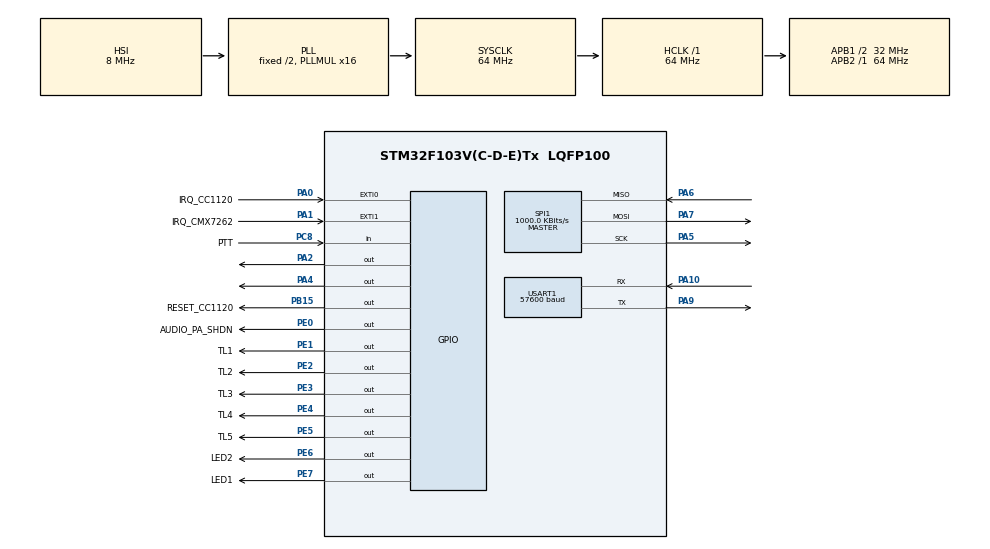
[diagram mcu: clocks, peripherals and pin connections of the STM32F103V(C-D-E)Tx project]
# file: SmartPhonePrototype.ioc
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Dma.Request0=USART1_RX
Dma.Request1=USART1_TX
Dma.Request2=SPI1_RX
Dma.Request3=SPI1_TX
Dma.SPI1_RX.2.Direction=DMA_PERIPH_TO_MEMORY
Dma.SPI1_RX.2.Instance=DMA1_Channel2
Dma.SPI1_RX.2.MemDataAlignment=DMA_MDATAALIGN_BYTE
Dma.SPI1_RX.2.MemInc=DMA_MINC_ENABLE
Dma.SPI1_RX.2.Mode=DMA_NORMAL
Dma.SPI1_RX.2.PeriphDataAlignment=DMA_PDATAALIGN_BYTE
Dma.SPI1_RX.2.PeriphInc=DMA_PINC_DISABLE
Dma.SPI1_RX.2.Priority=DMA_PRIORITY_LOW
Dma.SPI1_TX.3.Direction=DMA_MEMORY_TO_PERIPH
Dma.SPI1_TX.3.Instance=DMA1_Channel3
Dma.SPI1_TX.3.MemDataAlignment=DMA_MDATAALIGN_BYTE
Dma.SPI1_TX.3.MemInc=DMA_MINC_ENABLE
Dma.SPI1_TX.3.Mode=DMA_NORMAL
Dma.SPI1_TX.3.PeriphDataAlignment=DMA_PDATAALIGN_BYTE
Dma.SPI1_TX.3.PeriphInc=DMA_PINC_DISABLE
Dma.SPI1_TX.3.Priority=DMA_PRIORITY_LOW
Dma.USART1_RX.0.Direction=DMA_PERIPH_TO_MEMORY
Dma.USART1_RX.0.Instance=DMA1_Channel5
Dma.USART1_RX.0.MemDataAlignment=DMA_MDATAALIGN_BYTE
Dma.USART1_RX.0.MemInc=DMA_MINC_ENABLE
Dma.USART1_RX.0.Mode=DMA_NORMAL
Dma.USART1_RX.0.PeriphDataAlignment=DMA_PDATAALIGN_BYTE
Dma.USART1_RX.0.PeriphInc=DMA_PINC_DISABLE
Dma.USART1_RX.0.Priority=DMA_PRIORITY_LOW
Dma.USART1_TX.1.Direction=DMA_MEMORY_TO_PERIPH
Dma.USART1_TX.1.Instance=DMA1_Channel4
Dma.USART1_TX.1.MemDataAlignment=DMA_MDATAALIGN_BYTE
Dma.USART1_TX.1.MemInc=DMA_MINC_ENABLE
Dma.USART1_TX.1.Mode=DMA_NORMAL
Dma.USART1_TX.1.PeriphDataAlignment=DMA_PDATAALIGN_BYTE
Dma.USART1_TX.1.PeriphInc=DMA_PINC_DISABLE
Dma.USART1_TX.1.Priority=DMA_PRIORITY_LOW
Mcu.Family=STM32F1
Mcu.Name=STM32F103V(C-D-E)Tx
Mcu.Package=LQFP100
NVIC.DMA1_Channel2_IRQn=true\:0\:0\:false
NVIC.DMA1_Channel3_IRQn=true\:0\:0\:false
NVIC.DMA1_Channel4_IRQn=true\:0\:0\:false
NVIC.DMA1_Channel5_IRQn=true\:0\:0\:false
NVIC.EXTI0_IRQn=true\:0\:0\:false
NVIC.EXTI1_IRQn=true\:0\:0\:false
NVIC.PriorityGroup=NVIC_PRIORITYGROUP_4
NVIC.RCC_IRQn=true\:0\:0\:false
NVIC.SPI1_IRQn=true\:0\:0\:false
NVIC.USART1_IRQn=true\:0\:0\:false
PA0-WKUP.GPIO_Label=IRQ_CC1120
PA0-WKUP.GPIO_ModeDefaultEXTI=GPIO_MODE_IT_FALLING
PA0-WKUP.GPIO_PuPd=GPIO_PULLUP
PA0-WKUP.Signal=GPXTI0
PA1.GPIO_Label=IRQ_CMX7262
PA1.GPIO_ModeDefaultEXTI=GPIO_MODE_IT_FALLING
PA1.GPIO_PuPd=GPIO_PULLUP
PA1.Signal=GPXTI1
PA10.Mode=Asynchronous
PA10.Signal=USART1_RX
PA2.GPIO_Speed=GPIO_SPEED_HIGH
PA2.Signal=GPIO_Output
PA4.GPIO_Speed=GPIO_SPEED_HIGH
PA4.Signal=GPIO_Output
PA5.Mode=Full_Duplex_Master
PA5.Signal=SPI1_SCK
PA6.Mode=Full_Duplex_Master
PA6.Signal=SPI1_MISO
PA7.Mode=Full_Duplex_Master
PA7.Signal=SPI1_MOSI
PA9.Mode=Asynchronous
PA9.Signal=USART1_TX
PB15.GPIO_Label=RESET_CC1120
PB15.Signal=GPIO_Output
PC8.GPIO_Label=PTT
PC8.Signal=GPIO_Input
PE0.GPIO_Label=AUDIO_PA_SHDN
PE0.GPIO_Speed=GPIO_SPEED_HIGH
PE0.Signal=GPIO_Output
PE1.GPIO_Label=TL1
PE1.Signal=GPIO_Output
PE2.GPIO_Label=TL2
PE2.Signal=GPIO_Output
PE3.GPIO_Label=TL3
PE3.Signal=GPIO_Output
PE4.GPIO_Label=TL4
PE4.Signal=GPIO_Output
PE5.GPIO_Label=TL5
PE5.Signal=GPIO_Output
PE6.GPIO_Label=LED2
PE6.GPIO_Speed=GPIO_SPEED_HIGH
PE6.Signal=GPIO_Output
PE7.GPIO_Label=LED1
PE7.GPIO_Speed=GPIO_SPEED_HIGH
PE7.Signal=GPIO_Output
ProjectManager.TargetToolchain=MDK-ARM V5
RCC.AHBFreq_Value=64000000
RCC.APB1CLKDivider=RCC_HCLK_DIV2
RCC.APB1Freq_Value=32000000
RCC.APB1TimFreq_Value=64000000
RCC.APB2Freq_Value=64000000
RCC.APB2TimFreq_Value=64000000
RCC.HCLKFreq_Value=64000000
RCC.PLLMUL=RCC_PLL_MUL16
RCC.SYSCLKFreq_VALUE=64000000
RCC.SYSCLKSource=RCC_SYSCLKSOURCE_PLLCLK
RCC.USBFreq_Value=64000000
SPI1.BaudRatePrescaler=SPI_BAUDRATEPRESCALER_64
SPI1.CalculateBaudRate=1000.0 KBits/s
SPI1.Mode=SPI_MODE_MASTER
TIM2.Period=65535
TIM2.TIM_MasterOutputTrigger=TIM_TRGO_UPDATE
TIM2.TIM_MasterSlaveMode=TIM_MASTERSLAVEMODE_ENABLE
TIM3.Period=65535
TIM3.TIM_MasterSlaveMode=TIM_MASTERSLAVEMODE_DISABLE
TIM4.Period=65535
TIM5.Period=65535
USART1.BaudRate=57600
VP_TIM2_VS_ClockSourceINT.Mode=Internal
VP_TIM3_VS_ClockSourceITR.Mode=TriggerSource_ITR1
VP_TIM3_VS_ControllerModeClock.Mode=Clock Mode
VP_TIM4_VS_ClockSourceINT.Mode=Internal
VP_TIM5_VS_ClockSourceINT.Mode=Internal
board=SmartPhonePrototype

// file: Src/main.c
/**
  ******************************************************************************
  * File Name          : main.c
  * Description        : Main program body
  ******************************************************************************
  *
  * COPYRIGHT(c) 2016 STMicroelectronics
  *
  * Redistribution and use in source and binary forms, with or without modification,
  * are permitted provided that the following conditions are met:
  *   1. Redistributions of source code must retain the above copyright notice,
  *      this list of conditions and the following disclaimer.
  *   2. Redistributions in binary form must reproduce the above copyright notice,
  *      this list of conditions and the following disclaimer in the documentation
  *      and/or other materials provided with the distribution.
  *   3. Neither the name of STMicroelectronics nor the names of its contributors
  *      may be used to endorse or promote products derived from this software
  *      without specific prior written permission.
  *
  * THIS SOFTWARE IS PROVIDED BY THE COPYRIGHT HOLDERS AND CONTRIBUTORS "AS IS"
  * AND ANY EXPRESS OR IMPLIED WARRANTIES, INCLUDING, BUT NOT LIMITED TO, THE
  * IMPLIED WARRANTIES OF MERCHANTABILITY AND FITNESS FOR A PARTICULAR PURPOSE ARE
  * DISCLAIMED. IN NO EVENT SHALL THE COPYRIGHT HOLDER OR CONTRIBUTORS BE LIABLE
  * FOR ANY DIRECT, INDIRECT, INCIDENTAL, SPECIAL, EXEMPLARY, OR CONSEQUENTIAL
  * DAMAGES (INCLUDING, BUT NOT LIMITED TO, PROCUREMENT OF SUBSTITUTE GOODS OR
  * SERVICES; LOSS OF USE, DATA, OR PROFITS; OR BUSINESS INTERRUPTION) HOWEVER
  * CAUSED AND ON ANY THEORY OF LIABILITY, WHETHER IN CONTRACT, STRICT LIABILITY,
  * OR TORT (INCLUDING NEGLIGENCE OR OTHERWISE) ARISING IN ANY WAY OUT OF THE USE
  * OF THIS SOFTWARE, EVEN IF ADVISED OF THE POSSIBILITY OF SUCH DAMAGE.
  *
  ******************************************************************************
  */
#include "stm32f1xx_hal.h"

/* USER CODE BEGIN Includes */
#include "globals.h"
#include "cc1120.h"
#include "cmx7262.h"
#include "ProcessStates.h"
#include "SPIMLogic.h"
/* USER CODE END Includes */

SPI_HandleTypeDef hspi1;
DMA_HandleTypeDef hdma_spi1_rx;
DMA_HandleTypeDef hdma_spi1_tx;

TIM_HandleTypeDef htim2;
TIM_HandleTypeDef htim3;
TIM_HandleTypeDef htim4;
TIM_HandleTypeDef htim5;

UART_HandleTypeDef huart1;
DMA_HandleTypeDef hdma_usart1_rx;
DMA_HandleTypeDef hdma_usart1_tx;

/* USER CODE BEGIN PV */
/* Private variables ---------------------------------------------------------*/
extern UART_InitTypeDef DefaultUARTParams;

extern en_UARTstates UARTstate;

#define DMA_UART_PRIORITY (2)

/* USER CODE END PV */

void SystemClock_Config(void);
static void MX_GPIO_Init(void);
static void MX_DMA_Init(void);
static void MX_SPI1_Init(void);
static void MX_TIM2_Init(void);
static void MX_TIM3_Init(void);
static void MX_TIM4_Init(void);
static void MX_TIM5_Init(void);
static void MX_USART1_UART_Init(void);

/* USER CODE BEGIN PFP */
/* Private function prototypes -----------------------------------------------*/

/* USER CODE END PFP */

int main(void)
{
  /* USER CODE BEGIN 1 */
	#ifdef DEBUG_TRELLIS_CODER
	//TestTrellisCoder1_2();
	TestTrellisCoder3_4();
	#endif
  /* USER CODE END 1 */

  /* MCU Configuration----------------------------------------------------------*/

  /* Reset of all peripherals, Initializes the Flash interface and the Systick. */
  HAL_Init();

  /* Configure the system clock */
  SystemClock_Config();

  /* Initialize all configured peripherals */
  MX_GPIO_Init();
  MX_DMA_Init();
  MX_SPI1_Init();
  MX_TIM2_Init();
  MX_TIM3_Init();
  MX_TIM4_Init();
  MX_TIM5_Init();
  MX_USART1_UART_Init();

  /* USER CODE BEGIN 2 */
	// Устанавливаем CS периферийных микросхем в высокое состояние
	CC1120_CSN_HIGH();
	CMX7262_CSN_HIGH();

	// Pin Reset CC1120 устанавливаем в высокое состояние для перевода микросхемы в активное состояние
	CC1120_START();

	//Выключаем светодиоды
	LEDS_OFF();

	#ifdef DEBUG_USE_TL_LINES
	TLS_LOW();
	#endif

	//Запускаем таймеры для работы с периферией
	StartPeriphTimers();

	// Инициализируем работу по UART
	UART_InitInterface(&huart1);

	#ifdef DEBUG_CHECK_PERIPH_MODULES_ON_STARTUP	//Проверка работоспособности периферийных модулей
	CC1120_CheckModule(&hspi1);
	CMX7262_CheckModule(&hspi1);
	#endif

	//Делаем инициализацию радиомодуля для возможности управления его режимами и параметрами
	RadioModuleInit(&hspi1,&hspi1);

	#ifdef TEST_CMX7262
	CMX7262_TestMode();
	#endif

	#ifdef USE_LEDS
	//Сигнализируем о том, что модуль загрузился
	LED1_ON();
	#endif
  /* USER CODE END 2 */

  /* Infinite loop */
  /* USER CODE BEGIN WHILE */
  while (1)
  {
		//Если из UART приняты данные
		if(UARTstate==UART_DATA_RX_NEED_TO_PROCESS)
		{
			//Обрабатываем их
			ProcessDataFromExtDev();

			//Указываем, что данные обработаны
			UARTstate = UART_IDLE;
		}

		//Передача асинхронных данных (без непосредственного запроса от внешнего устройства)
		ProcessAsyncData();

		//Обработка состояния модуля CMX7262: передача/прием/тест
		ProcessCMX7262State();

		#ifndef TEST_CMX7262
		//Обрабатываем тангенту
		ProcessPTTState();

		ProcessRadioState();
		#endif

  /* USER CODE END WHILE */

  }

}

/** System Clock Configuration
*/
void SystemClock_Config(void)
{

  RCC_OscInitTypeDef RCC_OscInitStruct;
  RCC_ClkInitTypeDef RCC_ClkInitStruct;

  RCC_OscInitStruct.OscillatorType = RCC_OSCILLATORTYPE_HSI;
  RCC_OscInitStruct.HSIState = RCC_HSI_ON;
  RCC_OscInitStruct.HSICalibrationValue = 16;
  RCC_OscInitStruct.PLL.PLLState = RCC_PLL_ON;
  RCC_OscInitStruct.PLL.PLLSource = RCC_PLLSOURCE_HSI_DIV2;
  RCC_OscInitStruct.PLL.PLLMUL = RCC_PLL_MUL16;
  HAL_RCC_OscConfig(&RCC_OscInitStruct);

  RCC_ClkInitStruct.ClockType = RCC_CLOCKTYPE_SYSCLK|RCC_CLOCKTYPE_PCLK1;
  RCC_ClkInitStruct.SYSCLKSource = RCC_SYSCLKSOURCE_PLLCLK;
  RCC_ClkInitStruct.AHBCLKDivider = RCC_SYSCLK_DIV1;
  RCC_ClkInitStruct.APB1CLKDivider = RCC_HCLK_DIV2;
  RCC_ClkInitStruct.APB2CLKDivider = RCC_HCLK_DIV1;
  HAL_RCC_ClockConfig(&RCC_ClkInitStruct, FLASH_LATENCY_2);

  HAL_SYSTICK_Config(HAL_RCC_GetHCLKFreq()/1000);

  HAL_SYSTICK_CLKSourceConfig(SYSTICK_CLKSOURCE_HCLK);

  /* SysTick_IRQn interrupt configuration */
  HAL_NVIC_SetPriority(SysTick_IRQn, 0, 0);
}

/* SPI1 init function */
void MX_SPI1_Init(void)
{

  hspi1.Instance = SPI1;
  hspi1.Init.Mode = SPI_MODE_MASTER;
  hspi1.Init.Direction = SPI_DIRECTION_2LINES;						// режим работы: двухпроводный full duplex
  hspi1.Init.DataSize = SPI_DATASIZE_8BIT;								// размер данных - 8 бит
  hspi1.Init.CLKPolarity = SPI_POLARITY_LOW;
  hspi1.Init.CLKPhase = SPI_PHASE_1EDGE;									// синхронизация по заднему фронту
  hspi1.Init.NSS = SPI_NSS_SOFT;													// программный CS (аппаратный (SPI_NSS_HARD_OUTPUT) не понятно, как задействовать)
	hspi1.Init.BaudRatePrescaler = SPI_BAUDRATEPRESCALER_128 ;	//предделитель частоты SPI: 64МГц/128 = 500 кГц
  hspi1.Init.FirstBit = SPI_FIRSTBIT_MSB;									// старший бит - первый
  hspi1.Init.TIMode = SPI_TIMODE_DISABLED;
  hspi1.Init.CRCCalculation = SPI_CRCCALCULATION_DISABLED;// CRC не вычисляется
  hspi1.Init.CRCPolynomial = 10;
  HAL_SPI_Init(&hspi1);

}

/* Таймеры TIM2 и TIM3 реализуют высокоточный (точность - 1мкс) 32-битный таймер для оценки временных
интервалов в реализации низкоуровневых функций (передача байта по SPI, UART и т.п.) */

/* TIM2 init function */
void MX_TIM2_Init(void)
{

  TIM_ClockConfigTypeDef sClockSourceConfig;
  TIM_MasterConfigTypeDef sMasterConfig;

  htim2.Instance = TIM2;
  htim2.Init.Prescaler = (uint16_t) ((SystemCoreClock) / 1e6) - 1;		//такт таймера - в 1 мкс
  htim2.Init.CounterMode = TIM_COUNTERMODE_UP;
  htim2.Init.Period = 65535;
  htim2.Init.ClockDivision = TIM_CLOCKDIVISION_DIV1;
  HAL_TIM_Base_Init(&htim2);

  sClockSourceConfig.ClockSource = TIM_CLOCKSOURCE_INTERNAL;
  HAL_TIM_ConfigClockSource(&htim2, &sClockSourceConfig);

	//Таймер используется как master в каскадной цепочке таймеров для реализации 32-битного таймера
	//Слейвом выступает TIM3. Формируем для него сигнал тригера по истечению периода
  sMasterConfig.MasterOutputTrigger = TIM_TRGO_UPDATE;
  sMasterConfig.MasterSlaveMode = TIM_MASTERSLAVEMODE_ENABLE;
  HAL_TIMEx_MasterConfigSynchronization(&htim2, &sMasterConfig);

}

/* TIM3 init function */
void MX_TIM3_Init(void)
{

  TIM_SlaveConfigTypeDef sSlaveConfig;
  TIM_MasterConfigTypeDef sMasterConfig;

  htim3.Instance = TIM3;
  htim3.Init.Prescaler = 0;
  htim3.Init.CounterMode = TIM_COUNTERMODE_UP;
  htim3.Init.Period = 65535;
  htim3.Init.ClockDivision = TIM_CLOCKDIVISION_DIV1;
  HAL_TIM_Base_Init(&htim3);

	//Таймер используется как slave в каскадной цепочке таймеров для реализации 32-битного таймера
	//По переполнению счетчика master-таймера (TIM2) инкрементируется счетчик данного slave-таймера
	//Прерывание ITR1 используется как внешний тригер для инкрементирования значения счетчика
  sSlaveConfig.SlaveMode = TIM_SLAVEMODE_EXTERNAL1;
  sSlaveConfig.InputTrigger = TIM_TS_ITR1;
  HAL_TIM_SlaveConfigSynchronization(&htim3, &sSlaveConfig);

  sMasterConfig.MasterOutputTrigger = TIM_TRGO_RESET;
  sMasterConfig.MasterSlaveMode = TIM_MASTERSLAVEMODE_DISABLE;
  HAL_TIMEx_MasterConfigSynchronization(&htim3, &sMasterConfig);

}

/* TIM4 init function */
void MX_TIM4_Init(void)
{

  TIM_ClockConfigTypeDef sClockSourceConfig;
  TIM_MasterConfigTypeDef sMasterConfig;

  htim4.Instance = TIM4;
  htim4.Init.Prescaler = (uint16_t) ((SystemCoreClock)/1e5 - 1);	//такт таймера - в 10 мкс
  htim4.Init.CounterMode = TIM_COUNTERMODE_UP;
  htim4.Init.Period = 65535;
  htim4.Init.ClockDivision = TIM_CLOCKDIVISION_DIV1;
  HAL_TIM_Base_Init(&htim4);

  sClockSourceConfig.ClockSource = TIM_CLOCKSOURCE_INTERNAL;
  HAL_TIM_ConfigClockSource(&htim4, &sClockSourceConfig);

  sMasterConfig.MasterOutputTrigger = TIM_TRGO_RESET;
  sMasterConfig.MasterSlaveMode = TIM_MASTERSLAVEMODE_DISABLE;
  HAL_TIMEx_MasterConfigSynchronization(&htim4, &sMasterConfig);

}

/* TIM5 init function */
void MX_TIM5_Init(void)
{

  TIM_ClockConfigTypeDef sClockSourceConfig;
  TIM_MasterConfigTypeDef sMasterConfig;

  htim5.Instance = TIM5;
  htim5.Init.Prescaler = (uint16_t) ((SystemCoreClock)/1e5 - 1);	//такт таймера - в 10 мкс
  htim5.Init.CounterMode = TIM_COUNTERMODE_UP;
  htim5.Init.Period = 65535;
  htim5.Init.ClockDivision = TIM_CLOCKDIVISION_DIV1;
  HAL_TIM_Base_Init(&htim5);

  sClockSourceConfig.ClockSource = TIM_CLOCKSOURCE_INTERNAL;
  HAL_TIM_ConfigClockSource(&htim5, &sClockSourceConfig);

  sMasterConfig.MasterOutputTrigger = TIM_TRGO_RESET;
  sMasterConfig.MasterSlaveMode = TIM_MASTERSLAVEMODE_DISABLE;
  HAL_TIMEx_MasterConfigSynchronization(&htim5, &sMasterConfig);

}

/* USART1 init function */
void MX_USART1_UART_Init(void)
{
  huart1.Instance = USART1;
  huart1.Init = DefaultUARTParams;
  HAL_UART_Init(&huart1);

}

void MX_DMA_Init(void)
{
  /* DMA controller clock enable */
  __HAL_RCC_DMA1_CLK_ENABLE();

  /* DMA interrupt init */
  HAL_NVIC_SetPriority(DMA1_Channel2_IRQn, 0, 0);
  HAL_NVIC_EnableIRQ(DMA1_Channel2_IRQn);
  HAL_NVIC_SetPriority(DMA1_Channel3_IRQn, 0, 0);
  HAL_NVIC_EnableIRQ(DMA1_Channel3_IRQn);
  HAL_NVIC_SetPriority(DMA1_Channel4_IRQn, DMA_UART_PRIORITY, 0);
  HAL_NVIC_EnableIRQ(DMA1_Channel4_IRQn);
  HAL_NVIC_SetPriority(DMA1_Channel5_IRQn, DMA_UART_PRIORITY, 0);
  HAL_NVIC_EnableIRQ(DMA1_Channel5_IRQn);

}

/** Configure pins as
        * Analog
        * Input
        * Output
        * EVENT_OUT
        * EXTI
*/
void MX_GPIO_Init(void)
{

  GPIO_InitTypeDef GPIO_InitStruct;

  /* GPIO Ports Clock Enable */
  __GPIOE_CLK_ENABLE();
  __GPIOA_CLK_ENABLE();
  __GPIOB_CLK_ENABLE();
  __GPIOC_CLK_ENABLE();

  /*Configure GPIO pins : AUDIO_PA_SHDN */
  GPIO_InitStruct.Pin = AUDIO_PA_SHDN_Pin;
  GPIO_InitStruct.Mode = GPIO_MODE_OUTPUT_PP;
  GPIO_InitStruct.Speed = GPIO_SPEED_HIGH;
  HAL_GPIO_Init(AUDIO_PA_SHDN_GPIO_Port, &GPIO_InitStruct);

  /*Configure GPIO pins : PE1 PE2 PE3 PE4 PE5*/
  GPIO_InitStruct.Pin = TL1_Pin|TL2_Pin|TL3_Pin|TL4_Pin|TL5_Pin;
  GPIO_InitStruct.Mode = GPIO_MODE_OUTPUT_PP;
  GPIO_InitStruct.Speed = GPIO_SPEED_HIGH;
  HAL_GPIO_Init(GPIOE, &GPIO_InitStruct);

	/*Configure GPIO pins : LED1 LED2 */
	GPIO_InitStruct.Pin = LED1_Pin|LED2_Pin;
  GPIO_InitStruct.Mode = GPIO_MODE_OUTPUT_PP;
  GPIO_InitStruct.Speed = GPIO_SPEED_HIGH;
  HAL_GPIO_Init(GPIOE, &GPIO_InitStruct);

  /*Configure GPIO pins : IRQ_CC1120 IRQ_CMX7262 */
  GPIO_InitStruct.Pin = IRQ_CC1120_Pin|IRQ_CMX7262_Pin;
  GPIO_InitStruct.Mode = GPIO_MODE_IT_FALLING;
  GPIO_InitStruct.Pull = GPIO_PULLUP;
  HAL_GPIO_Init(GPIOA, &GPIO_InitStruct);

  /*Configure GPIO pins : CS_CC1120 CS_CMX7262 */
  GPIO_InitStruct.Pin = CS_CC1120_Pin|CS_CMX7262_Pin;
  GPIO_InitStruct.Mode = GPIO_MODE_OUTPUT_PP;
  GPIO_InitStruct.Speed = GPIO_SPEED_HIGH;
  HAL_GPIO_Init(GPIOA, &GPIO_InitStruct);

  /*Configure GPIO pin : PTT_Pin */
  GPIO_InitStruct.Pin = PTT_Pin;
  GPIO_InitStruct.Mode = GPIO_MODE_INPUT;
  GPIO_InitStruct.Pull = GPIO_PULLUP;
  HAL_GPIO_Init(PTT_GPIO_Port, &GPIO_InitStruct);

  /*Configure GPIO pin : RESET_CC1120 */
  GPIO_InitStruct.Pin = RESET_CC1120_Pin;
  GPIO_InitStruct.Mode = GPIO_MODE_OUTPUT_PP;
	GPIO_InitStruct.Pull = GPIO_PULLUP;
  GPIO_InitStruct.Speed = GPIO_SPEED_LOW;
  HAL_GPIO_Init(RESET_CC1120_GPIO_Port, &GPIO_InitStruct);

  /* EXTI interrupt init*/
  HAL_NVIC_SetPriority(EXTI0_IRQn, 0, 0);
  HAL_NVIC_EnableIRQ(EXTI0_IRQn);

  HAL_NVIC_SetPriority(EXTI1_IRQn, 0, 0);
  HAL_NVIC_EnableIRQ(EXTI1_IRQn);

}

/************************ (C) COPYRIGHT STMicroelectronics *****END OF FILE****/
